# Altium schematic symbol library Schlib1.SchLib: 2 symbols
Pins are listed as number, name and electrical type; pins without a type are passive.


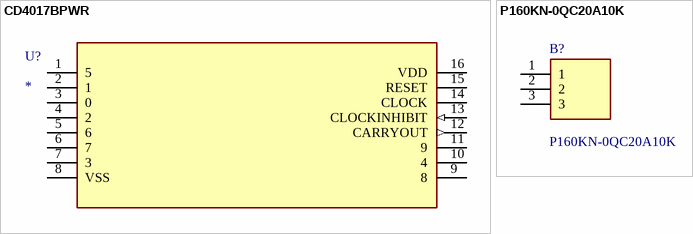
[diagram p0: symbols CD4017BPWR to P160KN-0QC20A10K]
## CD4017BPWR
designator U?
CMOS Decade Counter with 10 Decoded Outputs; MF: Texas Instruments; MP: CD4017BPWR
footprint PW16
pins: 1 5, 2 1, 3 0, 4 2, 5 6, 6 7, 7 3, 8 VSS (power), 9 8, 10 4, 11 9, 12 CARRYOUT (out), 13 CLOCKINHIBIT (in), 14 CLOCK, 15 RESET, 16 VDD (power)

## P160KN-0QC20A10K
designator B?
Potentiometers 16mm Rotary Panel Potentiometer; Manufacturer_Name: TT Electronics; Geometry.Height: 20.75mm
footprint P160KN0QC20A10K
pins: 1, 2, 3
